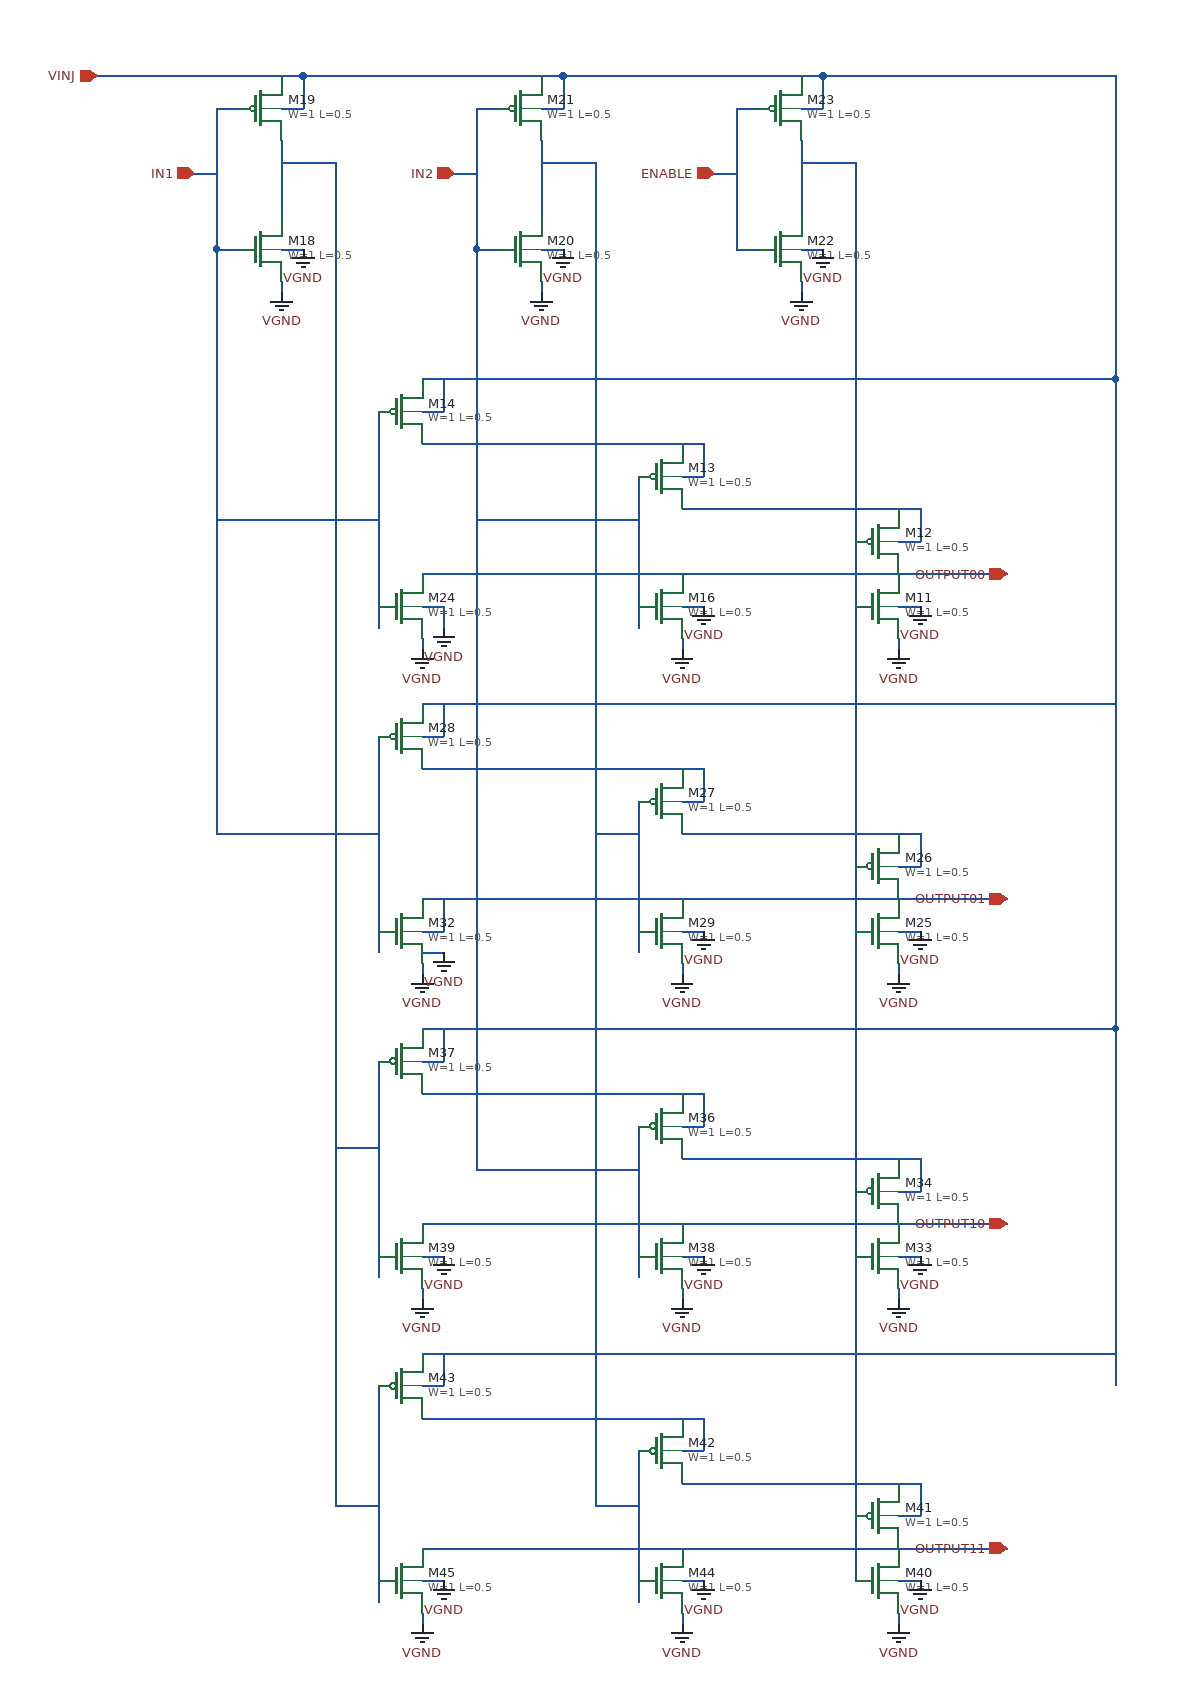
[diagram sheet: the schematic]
v {xschem version=2.9.9 file_version=1.2 }
G {}
K {}
V {}
S {}
E {}
N 2280 -1290 2280 -1220 { lab=#net1}
N 2280 -1320 2300 -1320 { lab=VINJ}
N 2300 -1350 2300 -1320 { lab=VINJ}
N 2280 -1350 2300 -1350 { lab=VINJ}
N 2110 -1350 2280 -1350 { lab=VINJ}
N 2280 -1160 2280 -1150 { lab=VGND}
N 2280 -1190 2300 -1190 { lab=VGND}
N 2280 -1270 2330 -1270 { lab=#net1}
N 2220 -1320 2220 -1190 { lab=IN1}
N 2220 -1190 2230 -1190 { lab=IN1}
N 2230 -1190 2240 -1190 { lab=IN1}
N 2200 -1260 2220 -1260 { lab=IN1}
N 2220 -1320 2240 -1320 { lab=IN1}
N 2520 -1290 2520 -1220 { lab=#net2}
N 2520 -1320 2540 -1320 { lab=VINJ}
N 2540 -1350 2540 -1320 { lab=VINJ}
N 2520 -1350 2540 -1350 { lab=VINJ}
N 2350 -1350 2520 -1350 { lab=VINJ}
N 2520 -1160 2520 -1150 { lab=VGND}
N 2520 -1190 2540 -1190 { lab=VGND}
N 2520 -1270 2570 -1270 { lab=#net2}
N 2460 -1320 2460 -1190 { lab=IN2}
N 2460 -1190 2470 -1190 { lab=IN2}
N 2470 -1190 2480 -1190 { lab=IN2}
N 2440 -1260 2460 -1260 { lab=IN2}
N 2460 -1320 2480 -1320 { lab=IN2}
N 2760 -1290 2760 -1220 { lab=#net3}
N 2760 -1320 2780 -1320 { lab=VINJ}
N 2780 -1350 2780 -1320 { lab=VINJ}
N 2760 -1350 2780 -1350 { lab=VINJ}
N 2590 -1350 2760 -1350 { lab=VINJ}
N 2760 -1160 2760 -1150 { lab=VGND}
N 2760 -1190 2780 -1190 { lab=VGND}
N 2760 -1270 2810 -1270 { lab=#net3}
N 2700 -1320 2700 -1190 { lab=ENABLE}
N 2700 -1190 2710 -1190 { lab=ENABLE}
N 2710 -1190 2720 -1190 { lab=ENABLE}
N 2680 -1260 2700 -1260 { lab=ENABLE}
N 2700 -1320 2720 -1320 { lab=ENABLE}
N 2300 -1350 2350 -1350 { lab=VINJ}
N 2540 -1350 2590 -1350 { lab=VINJ}
N 2520 -890 2950 -890 { lab=OUTPUT00}
N 2810 -1270 2810 -740 { lab=#net3}
N 2420 -1070 2700 -1070 { lab=VINJ}
N 2700 -1070 2850 -1070 { lab=VINJ}
N 2850 -1070 3050 -1070 { lab=VINJ}
N 3050 -1350 3050 -1070 { lab=VINJ}
N 2780 -1350 3050 -1350 { lab=VINJ}
N 2220 -1190 2220 -720 { lab=IN1}
N 2330 -1270 2330 -730 { lab=#net1}
N 2460 -1190 2460 -740 { lab=IN2}
N 2570 -1270 2570 -740 { lab=#net2}
N 2760 -950 2850 -950 { lab=#net4}
N 2410 -890 2650 -890 { lab=OUTPUT00}
N 2410 -830 2410 -820 { lab=VGND}
N 2650 -860 2670 -860 { lab=VGND}
N 2850 -860 2870 -860 { lab=VGND}
N 2610 -980 2610 -840 { lab=IN2}
N 2370 -1040 2370 -840 { lab=IN1}
N 2410 -1070 2420 -1070 { lab=VINJ}
N 2410 -1010 2420 -1010 { lab=#net5}
N 3050 -1040 3050 -760 { lab=VINJ}
N 2410 -1010 2650 -1010 { lab=#net5}
N 2650 -950 2770 -950 { lab=#net4}
N 3050 -1070 3050 -1040 { lab=VINJ}
N 2650 -830 2650 -820 { lab=VGND}
N 2850 -830 2850 -820 { lab=VGND}
N 2520 -590 2950 -590 { lab=OUTPUT01}
N 2420 -770 2700 -770 { lab=VINJ}
N 2700 -770 2850 -770 { lab=VINJ}
N 2850 -770 3050 -770 { lab=VINJ}
N 2760 -650 2850 -650 { lab=#net6}
N 2410 -590 2650 -590 { lab=OUTPUT01}
N 2410 -530 2410 -520 { lab=VGND}
N 2410 -540 2430 -540 { lab=VGND}
N 2650 -560 2670 -560 { lab=VGND}
N 2850 -560 2870 -560 { lab=VGND}
N 2610 -680 2610 -540 { lab=#net2}
N 2370 -740 2370 -540 { lab=IN1}
N 2410 -770 2420 -770 { lab=VINJ}
N 2410 -710 2420 -710 { lab=#net7}
N 2410 -710 2650 -710 { lab=#net7}
N 2650 -650 2770 -650 { lab=#net6}
N 3050 -770 3050 -740 { lab=VINJ}
N 2650 -530 2650 -520 { lab=VGND}
N 2850 -530 2850 -520 { lab=VGND}
N 2520 -290 2950 -290 { lab=OUTPUT10}
N 2420 -470 2700 -470 { lab=VINJ}
N 2700 -470 2850 -470 { lab=VINJ}
N 2850 -470 3050 -470 { lab=VINJ}
N 2760 -350 2850 -350 { lab=#net8}
N 2410 -290 2650 -290 { lab=OUTPUT10}
N 2410 -230 2410 -220 { lab=VGND}
N 2410 -260 2430 -260 { lab=VGND}
N 2650 -260 2670 -260 { lab=VGND}
N 2850 -260 2870 -260 { lab=VGND}
N 2610 -380 2610 -240 { lab=IN2}
N 2370 -440 2370 -240 { lab=#net1}
N 2410 -470 2420 -470 { lab=VINJ}
N 2410 -410 2420 -410 { lab=#net9}
N 3050 -440 3050 -160 { lab=VINJ}
N 2410 -410 2650 -410 { lab=#net9}
N 2650 -350 2770 -350 { lab=#net8}
N 3050 -470 3050 -440 { lab=VINJ}
N 2650 -230 2650 -220 { lab=VGND}
N 2850 -230 2850 -220 { lab=VGND}
N 2520 10 2950 10 { lab=OUTPUT11}
N 2420 -170 2700 -170 { lab=VINJ}
N 2700 -170 2850 -170 { lab=VINJ}
N 2850 -170 3050 -170 { lab=VINJ}
N 2760 -50 2850 -50 { lab=#net10}
N 2410 10 2650 10 { lab=OUTPUT11}
N 2410 70 2410 80 { lab=VGND}
N 2410 40 2430 40 { lab=VGND}
N 2650 40 2670 40 { lab=VGND}
N 2850 40 2870 40 { lab=VGND}
N 2610 -80 2610 60 { lab=#net2}
N 2370 -140 2370 60 { lab=#net1}
N 2410 -170 2420 -170 { lab=VINJ}
N 2410 -110 2420 -110 { lab=#net11}
N 2410 -110 2650 -110 { lab=#net11}
N 2650 -50 2770 -50 { lab=#net10}
N 3050 -170 3050 -140 { lab=VINJ}
N 2650 70 2650 80 { lab=VGND}
N 2850 70 2850 80 { lab=VGND}
N 3050 -740 3050 -480 { lab=VINJ}
N 3050 -480 3050 -470 { lab=VINJ}
N 2810 -320 2810 -260 { lab=#net3}
N 2810 -560 2810 -320 { lab=#net3}
N 2810 -620 2810 -560 { lab=#net3}
N 2810 -740 2810 -620 { lab=#net3}
N 2810 -20 2810 40 { lab=#net3}
N 2810 -260 2810 -20 { lab=#net3}
N 2220 -940 2370 -940 { lab=IN1}
N 2460 -940 2610 -940 { lab=IN2}
N 2460 -740 2460 -500 { lab=IN2}
N 2570 -740 2570 -510 { lab=#net2}
N 2220 -720 2220 -650 { lab=IN1}
N 2330 -730 2330 -510 { lab=#net1}
N 2220 -650 2370 -650 { lab=IN1}
N 2570 -650 2610 -650 { lab=#net2}
N 2330 -510 2330 -30 { lab=#net1}
N 2330 -30 2370 -30 { lab=#net1}
N 2330 -360 2370 -360 { lab=#net1}
N 2460 -500 2460 -340 { lab=IN2}
N 2460 -340 2610 -340 { lab=IN2}
N 2570 -510 2570 -220 { lab=#net2}
N 2570 -220 2570 -30 { lab=#net2}
N 2570 -30 2610 -30 { lab=#net2}
N 2410 -1040 2430 -1040 { lab=VINJ}
N 2430 -1070 2430 -1040 { lab=VINJ}
N 2410 -740 2430 -740 { lab=VINJ}
N 2430 -770 2430 -740 { lab=VINJ}
N 2410 -440 2430 -440 { lab=VINJ}
N 2430 -470 2430 -440 { lab=VINJ}
N 2410 -560 2430 -560 { lab=OUTPUT01}
N 2430 -590 2430 -560 { lab=OUTPUT01}
N 2410 -140 2430 -140 { lab=VINJ}
N 2430 -170 2430 -140 { lab=VINJ}
N 2650 -80 2670 -80 { lab=#net11}
N 2670 -110 2670 -80 { lab=#net11}
N 2650 -110 2670 -110 { lab=#net11}
N 2850 -20 2870 -20 { lab=#net10}
N 2870 -50 2870 -20 { lab=#net10}
N 2850 -50 2870 -50 { lab=#net10}
N 2850 -320 2870 -320 { lab=#net8}
N 2870 -350 2870 -320 { lab=#net8}
N 2850 -350 2870 -350 { lab=#net8}
N 2650 -380 2670 -380 { lab=#net9}
N 2670 -410 2670 -380 { lab=#net9}
N 2650 -410 2670 -410 { lab=#net9}
N 2850 -620 2870 -620 { lab=#net6}
N 2870 -650 2870 -620 { lab=#net6}
N 2850 -650 2870 -650 { lab=#net6}
N 2650 -680 2670 -680 { lab=#net7}
N 2670 -710 2670 -680 { lab=#net7}
N 2650 -710 2670 -710 { lab=#net7}
N 2850 -920 2870 -920 { lab=#net4}
N 2870 -950 2870 -920 { lab=#net4}
N 2850 -950 2870 -950 { lab=#net4}
N 2650 -980 2670 -980 { lab=#net5}
N 2670 -1010 2670 -980 { lab=#net5}
N 2650 -1010 2670 -1010 { lab=#net5}
N 2410 -860 2430 -860 { lab=VGND}
N 2430 -860 2430 -840 { lab=VGND}
C {devices/iopin.sym} 2950 -890 0 0 {name=OUTPUT00 lab=OUTPUT00}
C {devices/ipin.sym} 2110 -1350 0 0 {name=VINJ lab=VINJ}
C {sky130_fd_pr/nfet_g5v0d10v5.sym} 2830 -860 0 0 {name=M11
L=0.5
W=1
nf=1
mult=1
ad="'int((nf+1)/2) * W/nf * 0.29'" 
pd="'2*int((nf+1)/2) * (W/nf + 0.29)'"
as="'int((nf+2)/2) * W/nf * 0.29'" 
ps="'2*int((nf+2)/2) * (W/nf + 0.29)'"
nrd="'0.29 / W'" nrs="'0.29 / W'"
sa=0 sb=0 sd=0
model=nfet_g5v0d10v5
spiceprefix=X
}
C {sky130_fd_pr/pfet_g5v0d10v5.sym} 2830 -920 0 0 {name=M12
L=0.5
W=1
nf=1
mult=1
ad="'int((nf+1)/2) * W/nf * 0.29'" 
pd="'2*int((nf+1)/2) * (W/nf + 0.29)'"
as="'int((nf+2)/2) * W/nf * 0.29'" 
ps="'2*int((nf+2)/2) * (W/nf + 0.29)'"
nrd="'0.29 / W'" nrs="'0.29 / W'"
sa=0 sb=0 sd=0
model=pfet_g5v0d10v5
spiceprefix=X
}
C {sky130_fd_pr/pfet_g5v0d10v5.sym} 2630 -980 0 0 {name=M13
L=0.5
W=1
nf=1
mult=1
ad="'int((nf+1)/2) * W/nf * 0.29'" 
pd="'2*int((nf+1)/2) * (W/nf + 0.29)'"
as="'int((nf+2)/2) * W/nf * 0.29'" 
ps="'2*int((nf+2)/2) * (W/nf + 0.29)'"
nrd="'0.29 / W'" nrs="'0.29 / W'"
sa=0 sb=0 sd=0
model=pfet_g5v0d10v5
spiceprefix=X
}
C {sky130_fd_pr/pfet_g5v0d10v5.sym} 2390 -1040 0 0 {name=M14
L=0.5
W=1
nf=1
mult=1
ad="'int((nf+1)/2) * W/nf * 0.29'" 
pd="'2*int((nf+1)/2) * (W/nf + 0.29)'"
as="'int((nf+2)/2) * W/nf * 0.29'" 
ps="'2*int((nf+2)/2) * (W/nf + 0.29)'"
nrd="'0.29 / W'" nrs="'0.29 / W'"
sa=0 sb=0 sd=0
model=pfet_g5v0d10v5
spiceprefix=X
}
C {devices/ipin.sym} 2200 -1260 0 0 {name=IN1 lab=IN1}
C {sky130_fd_pr/nfet_g5v0d10v5.sym} 2260 -1190 0 0 {name=M18
L=0.5
W=1
nf=1
mult=1
ad="'int((nf+1)/2) * W/nf * 0.29'" 
pd="'2*int((nf+1)/2) * (W/nf + 0.29)'"
as="'int((nf+2)/2) * W/nf * 0.29'" 
ps="'2*int((nf+2)/2) * (W/nf + 0.29)'"
nrd="'0.29 / W'" nrs="'0.29 / W'"
sa=0 sb=0 sd=0
model=nfet_g5v0d10v5
spiceprefix=X
}
C {sky130_fd_pr/pfet_g5v0d10v5.sym} 2260 -1320 0 0 {name=M19
L=0.5
W=1
nf=1
mult=1
ad="'int((nf+1)/2) * W/nf * 0.29'" 
pd="'2*int((nf+1)/2) * (W/nf + 0.29)'"
as="'int((nf+2)/2) * W/nf * 0.29'" 
ps="'2*int((nf+2)/2) * (W/nf + 0.29)'"
nrd="'0.29 / W'" nrs="'0.29 / W'"
sa=0 sb=0 sd=0
model=pfet_g5v0d10v5
spiceprefix=X
}
C {devices/gnd.sym} 2300 -1190 0 0 {name=l13 lab=VGND}
C {devices/gnd.sym} 2280 -1150 0 0 {name=l14 lab=VGND}
C {devices/ipin.sym} 2440 -1260 0 0 {name=IN2 lab=IN2}
C {sky130_fd_pr/nfet_g5v0d10v5.sym} 2500 -1190 0 0 {name=M20
L=0.5
W=1
nf=1
mult=1
ad="'int((nf+1)/2) * W/nf * 0.29'" 
pd="'2*int((nf+1)/2) * (W/nf + 0.29)'"
as="'int((nf+2)/2) * W/nf * 0.29'" 
ps="'2*int((nf+2)/2) * (W/nf + 0.29)'"
nrd="'0.29 / W'" nrs="'0.29 / W'"
sa=0 sb=0 sd=0
model=nfet_g5v0d10v5
spiceprefix=X
}
C {sky130_fd_pr/pfet_g5v0d10v5.sym} 2500 -1320 0 0 {name=M21
L=0.5
W=1
nf=1
mult=1
ad="'int((nf+1)/2) * W/nf * 0.29'" 
pd="'2*int((nf+1)/2) * (W/nf + 0.29)'"
as="'int((nf+2)/2) * W/nf * 0.29'" 
ps="'2*int((nf+2)/2) * (W/nf + 0.29)'"
nrd="'0.29 / W'" nrs="'0.29 / W'"
sa=0 sb=0 sd=0
model=pfet_g5v0d10v5
spiceprefix=X
}
C {devices/gnd.sym} 2540 -1190 0 0 {name=l15 lab=VGND}
C {devices/gnd.sym} 2520 -1150 0 0 {name=l16 lab=VGND}
C {devices/ipin.sym} 2680 -1260 0 0 {name=ENABLE lab=ENABLE}
C {sky130_fd_pr/nfet_g5v0d10v5.sym} 2740 -1190 0 0 {name=M22
L=0.5
W=1
nf=1
mult=1
ad="'int((nf+1)/2) * W/nf * 0.29'" 
pd="'2*int((nf+1)/2) * (W/nf + 0.29)'"
as="'int((nf+2)/2) * W/nf * 0.29'" 
ps="'2*int((nf+2)/2) * (W/nf + 0.29)'"
nrd="'0.29 / W'" nrs="'0.29 / W'"
sa=0 sb=0 sd=0
model=nfet_g5v0d10v5
spiceprefix=X
}
C {sky130_fd_pr/pfet_g5v0d10v5.sym} 2740 -1320 0 0 {name=M23
L=0.5
W=1
nf=1
mult=1
ad="'int((nf+1)/2) * W/nf * 0.29'" 
pd="'2*int((nf+1)/2) * (W/nf + 0.29)'"
as="'int((nf+2)/2) * W/nf * 0.29'" 
ps="'2*int((nf+2)/2) * (W/nf + 0.29)'"
nrd="'0.29 / W'" nrs="'0.29 / W'"
sa=0 sb=0 sd=0
model=pfet_g5v0d10v5
spiceprefix=X
}
C {devices/gnd.sym} 2780 -1190 0 0 {name=l17 lab=VGND}
C {devices/gnd.sym} 2760 -1150 0 0 {name=l18 lab=VGND}
C {sky130_fd_pr/nfet_g5v0d10v5.sym} 2630 -860 0 0 {name=M16
L=0.5
W=1
nf=1
mult=1
ad="'int((nf+1)/2) * W/nf * 0.29'" 
pd="'2*int((nf+1)/2) * (W/nf + 0.29)'"
as="'int((nf+2)/2) * W/nf * 0.29'" 
ps="'2*int((nf+2)/2) * (W/nf + 0.29)'"
nrd="'0.29 / W'" nrs="'0.29 / W'"
sa=0 sb=0 sd=0
model=nfet_g5v0d10v5
spiceprefix=X
}
C {sky130_fd_pr/nfet_g5v0d10v5.sym} 2390 -860 0 0 {name=M24
L=0.5
W=1
nf=1
mult=1
ad="'int((nf+1)/2) * W/nf * 0.29'" 
pd="'2*int((nf+1)/2) * (W/nf + 0.29)'"
as="'int((nf+2)/2) * W/nf * 0.29'" 
ps="'2*int((nf+2)/2) * (W/nf + 0.29)'"
nrd="'0.29 / W'" nrs="'0.29 / W'"
sa=0 sb=0 sd=0
model=nfet_g5v0d10v5
spiceprefix=X
}
C {devices/gnd.sym} 2410 -820 0 0 {name=l19 lab=VGND}
C {devices/gnd.sym} 2430 -840 0 0 {name=l20 lab=VGND}
C {devices/gnd.sym} 2670 -860 0 0 {name=l21 lab=VGND}
C {devices/gnd.sym} 2870 -860 0 0 {name=l22 lab=VGND}
C {devices/gnd.sym} 2650 -820 0 0 {name=l23 lab=VGND}
C {devices/gnd.sym} 2850 -820 0 0 {name=l24 lab=VGND}
C {devices/iopin.sym} 2950 -590 0 0 {name=OUTPUT01 lab=OUTPUT01}
C {sky130_fd_pr/nfet_g5v0d10v5.sym} 2830 -560 0 0 {name=M25
L=0.5
W=1
nf=1
mult=1
ad="'int((nf+1)/2) * W/nf * 0.29'" 
pd="'2*int((nf+1)/2) * (W/nf + 0.29)'"
as="'int((nf+2)/2) * W/nf * 0.29'" 
ps="'2*int((nf+2)/2) * (W/nf + 0.29)'"
nrd="'0.29 / W'" nrs="'0.29 / W'"
sa=0 sb=0 sd=0
model=nfet_g5v0d10v5
spiceprefix=X
}
C {sky130_fd_pr/pfet_g5v0d10v5.sym} 2830 -620 0 0 {name=M26
L=0.5
W=1
nf=1
mult=1
ad="'int((nf+1)/2) * W/nf * 0.29'" 
pd="'2*int((nf+1)/2) * (W/nf + 0.29)'"
as="'int((nf+2)/2) * W/nf * 0.29'" 
ps="'2*int((nf+2)/2) * (W/nf + 0.29)'"
nrd="'0.29 / W'" nrs="'0.29 / W'"
sa=0 sb=0 sd=0
model=pfet_g5v0d10v5
spiceprefix=X
}
C {sky130_fd_pr/pfet_g5v0d10v5.sym} 2630 -680 0 0 {name=M27
L=0.5
W=1
nf=1
mult=1
ad="'int((nf+1)/2) * W/nf * 0.29'" 
pd="'2*int((nf+1)/2) * (W/nf + 0.29)'"
as="'int((nf+2)/2) * W/nf * 0.29'" 
ps="'2*int((nf+2)/2) * (W/nf + 0.29)'"
nrd="'0.29 / W'" nrs="'0.29 / W'"
sa=0 sb=0 sd=0
model=pfet_g5v0d10v5
spiceprefix=X
}
C {sky130_fd_pr/pfet_g5v0d10v5.sym} 2390 -740 0 0 {name=M28
L=0.5
W=1
nf=1
mult=1
ad="'int((nf+1)/2) * W/nf * 0.29'" 
pd="'2*int((nf+1)/2) * (W/nf + 0.29)'"
as="'int((nf+2)/2) * W/nf * 0.29'" 
ps="'2*int((nf+2)/2) * (W/nf + 0.29)'"
nrd="'0.29 / W'" nrs="'0.29 / W'"
sa=0 sb=0 sd=0
model=pfet_g5v0d10v5
spiceprefix=X
}
C {sky130_fd_pr/nfet_g5v0d10v5.sym} 2630 -560 0 0 {name=M29
L=0.5
W=1
nf=1
mult=1
ad="'int((nf+1)/2) * W/nf * 0.29'" 
pd="'2*int((nf+1)/2) * (W/nf + 0.29)'"
as="'int((nf+2)/2) * W/nf * 0.29'" 
ps="'2*int((nf+2)/2) * (W/nf + 0.29)'"
nrd="'0.29 / W'" nrs="'0.29 / W'"
sa=0 sb=0 sd=0
model=nfet_g5v0d10v5
spiceprefix=X
}
C {sky130_fd_pr/nfet_g5v0d10v5.sym} 2390 -560 0 0 {name=M32
L=0.5
W=1
nf=1
mult=1
ad="'int((nf+1)/2) * W/nf * 0.29'" 
pd="'2*int((nf+1)/2) * (W/nf + 0.29)'"
as="'int((nf+2)/2) * W/nf * 0.29'" 
ps="'2*int((nf+2)/2) * (W/nf + 0.29)'"
nrd="'0.29 / W'" nrs="'0.29 / W'"
sa=0 sb=0 sd=0
model=nfet_g5v0d10v5
spiceprefix=X
}
C {devices/gnd.sym} 2410 -520 0 0 {name=l25 lab=VGND}
C {devices/gnd.sym} 2430 -540 0 0 {name=l26 lab=VGND}
C {devices/gnd.sym} 2670 -560 0 0 {name=l27 lab=VGND}
C {devices/gnd.sym} 2870 -560 0 0 {name=l28 lab=VGND}
C {devices/gnd.sym} 2650 -520 0 0 {name=l29 lab=VGND}
C {devices/gnd.sym} 2850 -520 0 0 {name=l30 lab=VGND}
C {devices/iopin.sym} 2950 -290 0 0 {name=OUTPUT10 lab=OUTPUT10}
C {sky130_fd_pr/nfet_g5v0d10v5.sym} 2830 -260 0 0 {name=M33
L=0.5
W=1
nf=1
mult=1
ad="'int((nf+1)/2) * W/nf * 0.29'" 
pd="'2*int((nf+1)/2) * (W/nf + 0.29)'"
as="'int((nf+2)/2) * W/nf * 0.29'" 
ps="'2*int((nf+2)/2) * (W/nf + 0.29)'"
nrd="'0.29 / W'" nrs="'0.29 / W'"
sa=0 sb=0 sd=0
model=nfet_g5v0d10v5
spiceprefix=X
}
C {sky130_fd_pr/pfet_g5v0d10v5.sym} 2830 -320 0 0 {name=M34
L=0.5
W=1
nf=1
mult=1
ad="'int((nf+1)/2) * W/nf * 0.29'" 
pd="'2*int((nf+1)/2) * (W/nf + 0.29)'"
as="'int((nf+2)/2) * W/nf * 0.29'" 
ps="'2*int((nf+2)/2) * (W/nf + 0.29)'"
nrd="'0.29 / W'" nrs="'0.29 / W'"
sa=0 sb=0 sd=0
model=pfet_g5v0d10v5
spiceprefix=X
}
C {sky130_fd_pr/pfet_g5v0d10v5.sym} 2630 -380 0 0 {name=M36
L=0.5
W=1
nf=1
mult=1
ad="'int((nf+1)/2) * W/nf * 0.29'" 
pd="'2*int((nf+1)/2) * (W/nf + 0.29)'"
as="'int((nf+2)/2) * W/nf * 0.29'" 
ps="'2*int((nf+2)/2) * (W/nf + 0.29)'"
nrd="'0.29 / W'" nrs="'0.29 / W'"
sa=0 sb=0 sd=0
model=pfet_g5v0d10v5
spiceprefix=X
}
C {sky130_fd_pr/pfet_g5v0d10v5.sym} 2390 -440 0 0 {name=M37
L=0.5
W=1
nf=1
mult=1
ad="'int((nf+1)/2) * W/nf * 0.29'" 
pd="'2*int((nf+1)/2) * (W/nf + 0.29)'"
as="'int((nf+2)/2) * W/nf * 0.29'" 
ps="'2*int((nf+2)/2) * (W/nf + 0.29)'"
nrd="'0.29 / W'" nrs="'0.29 / W'"
sa=0 sb=0 sd=0
model=pfet_g5v0d10v5
spiceprefix=X
}
C {sky130_fd_pr/nfet_g5v0d10v5.sym} 2630 -260 0 0 {name=M38
L=0.5
W=1
nf=1
mult=1
ad="'int((nf+1)/2) * W/nf * 0.29'" 
pd="'2*int((nf+1)/2) * (W/nf + 0.29)'"
as="'int((nf+2)/2) * W/nf * 0.29'" 
ps="'2*int((nf+2)/2) * (W/nf + 0.29)'"
nrd="'0.29 / W'" nrs="'0.29 / W'"
sa=0 sb=0 sd=0
model=nfet_g5v0d10v5
spiceprefix=X
}
C {sky130_fd_pr/nfet_g5v0d10v5.sym} 2390 -260 0 0 {name=M39
L=0.5
W=1
nf=1
mult=1
ad="'int((nf+1)/2) * W/nf * 0.29'" 
pd="'2*int((nf+1)/2) * (W/nf + 0.29)'"
as="'int((nf+2)/2) * W/nf * 0.29'" 
ps="'2*int((nf+2)/2) * (W/nf + 0.29)'"
nrd="'0.29 / W'" nrs="'0.29 / W'"
sa=0 sb=0 sd=0
model=nfet_g5v0d10v5
spiceprefix=X
}
C {devices/gnd.sym} 2410 -220 0 0 {name=l31 lab=VGND}
C {devices/gnd.sym} 2430 -260 0 0 {name=l32 lab=VGND}
C {devices/gnd.sym} 2670 -260 0 0 {name=l33 lab=VGND}
C {devices/gnd.sym} 2870 -260 0 0 {name=l34 lab=VGND}
C {devices/gnd.sym} 2650 -220 0 0 {name=l35 lab=VGND}
C {devices/gnd.sym} 2850 -220 0 0 {name=l36 lab=VGND}
C {devices/iopin.sym} 2950 10 0 0 {name=OUTPUT11 lab=OUTPUT11}
C {sky130_fd_pr/nfet_g5v0d10v5.sym} 2830 40 0 0 {name=M40
L=0.5
W=1
nf=1
mult=1
ad="'int((nf+1)/2) * W/nf * 0.29'" 
pd="'2*int((nf+1)/2) * (W/nf + 0.29)'"
as="'int((nf+2)/2) * W/nf * 0.29'" 
ps="'2*int((nf+2)/2) * (W/nf + 0.29)'"
nrd="'0.29 / W'" nrs="'0.29 / W'"
sa=0 sb=0 sd=0
model=nfet_g5v0d10v5
spiceprefix=X
}
C {sky130_fd_pr/pfet_g5v0d10v5.sym} 2830 -20 0 0 {name=M41
L=0.5
W=1
nf=1
mult=1
ad="'int((nf+1)/2) * W/nf * 0.29'" 
pd="'2*int((nf+1)/2) * (W/nf + 0.29)'"
as="'int((nf+2)/2) * W/nf * 0.29'" 
ps="'2*int((nf+2)/2) * (W/nf + 0.29)'"
nrd="'0.29 / W'" nrs="'0.29 / W'"
sa=0 sb=0 sd=0
model=pfet_g5v0d10v5
spiceprefix=X
}
C {sky130_fd_pr/pfet_g5v0d10v5.sym} 2630 -80 0 0 {name=M42
L=0.5
W=1
nf=1
mult=1
ad="'int((nf+1)/2) * W/nf * 0.29'" 
pd="'2*int((nf+1)/2) * (W/nf + 0.29)'"
as="'int((nf+2)/2) * W/nf * 0.29'" 
ps="'2*int((nf+2)/2) * (W/nf + 0.29)'"
nrd="'0.29 / W'" nrs="'0.29 / W'"
sa=0 sb=0 sd=0
model=pfet_g5v0d10v5
spiceprefix=X
}
C {sky130_fd_pr/pfet_g5v0d10v5.sym} 2390 -140 0 0 {name=M43
L=0.5
W=1
nf=1
mult=1
ad="'int((nf+1)/2) * W/nf * 0.29'" 
pd="'2*int((nf+1)/2) * (W/nf + 0.29)'"
as="'int((nf+2)/2) * W/nf * 0.29'" 
ps="'2*int((nf+2)/2) * (W/nf + 0.29)'"
nrd="'0.29 / W'" nrs="'0.29 / W'"
sa=0 sb=0 sd=0
model=pfet_g5v0d10v5
spiceprefix=X
}
C {sky130_fd_pr/nfet_g5v0d10v5.sym} 2630 40 0 0 {name=M44
L=0.5
W=1
nf=1
mult=1
ad="'int((nf+1)/2) * W/nf * 0.29'" 
pd="'2*int((nf+1)/2) * (W/nf + 0.29)'"
as="'int((nf+2)/2) * W/nf * 0.29'" 
ps="'2*int((nf+2)/2) * (W/nf + 0.29)'"
nrd="'0.29 / W'" nrs="'0.29 / W'"
sa=0 sb=0 sd=0
model=nfet_g5v0d10v5
spiceprefix=X
}
C {sky130_fd_pr/nfet_g5v0d10v5.sym} 2390 40 0 0 {name=M45
L=0.5
W=1
nf=1
mult=1
ad="'int((nf+1)/2) * W/nf * 0.29'" 
pd="'2*int((nf+1)/2) * (W/nf + 0.29)'"
as="'int((nf+2)/2) * W/nf * 0.29'" 
ps="'2*int((nf+2)/2) * (W/nf + 0.29)'"
nrd="'0.29 / W'" nrs="'0.29 / W'"
sa=0 sb=0 sd=0
model=nfet_g5v0d10v5
spiceprefix=X
}
C {devices/gnd.sym} 2410 80 0 0 {name=l37 lab=VGND}
C {devices/gnd.sym} 2430 40 0 0 {name=l38 lab=VGND}
C {devices/gnd.sym} 2670 40 0 0 {name=l39 lab=VGND}
C {devices/gnd.sym} 2870 40 0 0 {name=l40 lab=VGND}
C {devices/gnd.sym} 2650 80 0 0 {name=l41 lab=VGND}
C {devices/gnd.sym} 2850 80 0 0 {name=l42 lab=VGND}
